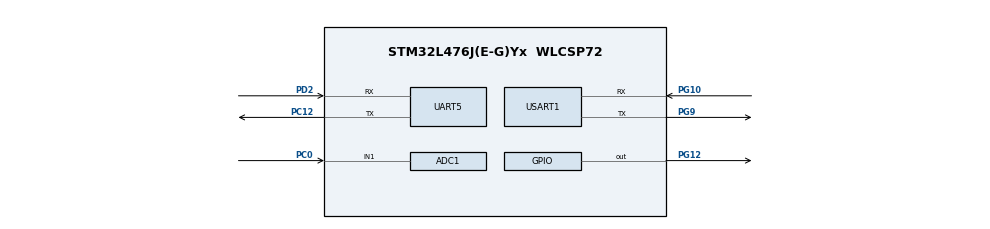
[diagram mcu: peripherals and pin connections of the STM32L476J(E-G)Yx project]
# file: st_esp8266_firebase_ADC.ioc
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ADC1.Channel-1\#ChannelRegularConversion=ADC_CHANNEL_1
ADC1.NbrOfConversionFlag=1
ADC1.OffsetNumber-1\#ChannelRegularConversion=ADC_OFFSET_NONE
ADC1.Rank-1\#ChannelRegularConversion=1
ADC1.SamplingTime-1\#ChannelRegularConversion=ADC_SAMPLETIME_2CYCLES_5
ADC1.master=1
Mcu.Family=STM32L4
Mcu.Name=STM32L476J(E-G)Yx
Mcu.Package=WLCSP72
NVIC.PriorityGroup=NVIC_PRIORITYGROUP_4
NVIC.UART5_IRQn=true\:0\:0\:false\:false\:true\:true\:true
NVIC.USART1_IRQn=true\:0\:0\:false\:false\:true\:true\:true
PC0.Signal=ADCx_IN1
PC12.Mode=Asynchronous
PC12.Signal=UART5_TX
PD2.Mode=Asynchronous
PD2.Signal=UART5_RX
PG10.Mode=Asynchronous
PG10.Signal=USART1_RX
PG12.Signal=GPIO_Output
PG9.Mode=Asynchronous
PG9.Signal=USART1_TX
PH0-OSC_IN\ (PH0).Mode=HSE-External-Oscillator
PH0-OSC_IN\ (PH0).Signal=RCC_OSC_IN
PH1-OSC_OUT\ (PH1).Mode=HSE-External-Oscillator
PH1-OSC_OUT\ (PH1).Signal=RCC_OSC_OUT
ProjectManager.HeapSize=0x200
ProjectManager.StackSize=0x400
ProjectManager.TargetToolchain=SW4STM32
RCC.ADCFreq_Value=32000000
RCC.AHBFreq_Value=50000000
RCC.APB1Freq_Value=50000000
RCC.APB1TimFreq_Value=50000000
RCC.APB2Freq_Value=50000000
RCC.APB2TimFreq_Value=50000000
RCC.CortexFreq_Value=50000000
RCC.HCLKFreq_Value=50000000
RCC.HSE_VALUE=8000000
RCC.HSI_VALUE=16000000
RCC.LSE_VALUE=32768
RCC.MSI_VALUE=4000000
RCC.PLLN=25
RCC.PLLSAI1N=16
RCC.SYSCLKFreq_VALUE=50000000
RCC.SYSCLKSource=RCC_SYSCLKSOURCE_PLLCLK
RCC.USBFreq_Value=32000000
RCC.VCOOutputFreq_Value=100000000
SH.ADCx_IN1.0=ADC1_IN1,IN1-Single-Ended
USART1.VirtualMode-Asynchronous=VM_ASYNC
board=custom

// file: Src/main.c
/* USER CODE BEGIN Header */
/**
 ******************************************************************************
 * @file           : main.c
 * @brief          : Main program body
 ******************************************************************************
 * @attention
 *
 * <h2><center>&copy; Copyright (c) 2020 STMicroelectronics.
 * All rights reserved.</center></h2>
 *
 * This software component is licensed by ST under BSD 3-Clause license,
 * the "License"; You may not use this file except in compliance with the
 * License. You may obtain a copy of the License at:
 *                        opensource.org/licenses/BSD-3-Clause
 *
 ******************************************************************************
 */
/* USER CODE END Header */

#include "main.h"
#include "ESPDataLogger.h"

ADC_HandleTypeDef hadc1;

UART_HandleTypeDef huart5;
UART_HandleTypeDef huart1;

void SystemClock_Config(void);
static void MX_GPIO_Init(void);
static void MX_ADC1_Init(void);
static void MX_USART1_UART_Init(void);
static void MX_UART5_Init(void);

/* USER CODE BEGIN 0 */
uint16_t ADC_Get_Value(void);

float Voltage = 0;
uint16_t ADC_Value = 0;
uint8_t count = 0;

uint16_t Value_Buf[4];

/* USER CODE END 0 */

int main(void) {

    /* MCU Configuration--------------------------------------------------------*/

    /* Reset of all peripherals, Initializes the Flash interface and the Systick. */
    HAL_Init();

    /* Configure the system clock */
    SystemClock_Config();

    /* Initialize all configured peripherals */
    MX_GPIO_Init();
    MX_ADC1_Init();
    MX_USART1_UART_Init();
    MX_UART5_Init();
    /* USER CODE BEGIN 2 */
    ESP_Init("test", "12345678");
    /* USER CODE END 2 */

    /* Infinite loop */
    while (1) {

        /* USER CODE BEGIN 3 */
        ADC_Value = ADC_Get_Value();
        Voltage = ((float) ADC_Value * 3.3 / 4095);
        count++;
        Value_Buf[0] = ADC_Value;
        Value_Buf[1] = Voltage;
        Value_Buf[2] = count;
        Value_Buf[3] = count * 2;

        ESP_Send_Multi(Value_Buf);

//        HAL_Delay(15000);
    }
    /* USER CODE END 3 */
}

void SystemClock_Config(void) {
    RCC_OscInitTypeDef RCC_OscInitStruct = { 0 };
    RCC_ClkInitTypeDef RCC_ClkInitStruct = { 0 };
    RCC_PeriphCLKInitTypeDef PeriphClkInit = { 0 };

    /** Initializes the CPU, AHB and APB busses clocks
     */
    RCC_OscInitStruct.OscillatorType = RCC_OSCILLATORTYPE_MSI;
    RCC_OscInitStruct.MSIState = RCC_MSI_ON;
    RCC_OscInitStruct.MSICalibrationValue = 0;
    RCC_OscInitStruct.MSIClockRange = RCC_MSIRANGE_6;
    RCC_OscInitStruct.PLL.PLLState = RCC_PLL_ON;
    RCC_OscInitStruct.PLL.PLLSource = RCC_PLLSOURCE_MSI;
    RCC_OscInitStruct.PLL.PLLM = 1;
    RCC_OscInitStruct.PLL.PLLN = 25;
    RCC_OscInitStruct.PLL.PLLP = RCC_PLLP_DIV7;
    RCC_OscInitStruct.PLL.PLLQ = RCC_PLLQ_DIV2;
    RCC_OscInitStruct.PLL.PLLR = RCC_PLLR_DIV2;
    if (HAL_RCC_OscConfig(&RCC_OscInitStruct) != HAL_OK) {
        Error_Handler();
    }
    /** Initializes the CPU, AHB and APB busses clocks
     */
    RCC_ClkInitStruct.ClockType = RCC_CLOCKTYPE_HCLK | RCC_CLOCKTYPE_SYSCLK
            | RCC_CLOCKTYPE_PCLK1 | RCC_CLOCKTYPE_PCLK2;
    RCC_ClkInitStruct.SYSCLKSource = RCC_SYSCLKSOURCE_PLLCLK;
    RCC_ClkInitStruct.AHBCLKDivider = RCC_SYSCLK_DIV2;
    RCC_ClkInitStruct.APB1CLKDivider = RCC_HCLK_DIV1;
    RCC_ClkInitStruct.APB2CLKDivider = RCC_HCLK_DIV1;

    if (HAL_RCC_ClockConfig(&RCC_ClkInitStruct, FLASH_LATENCY_1) != HAL_OK) {
        Error_Handler();
    }
    PeriphClkInit.PeriphClockSelection = RCC_PERIPHCLK_USART1
            | RCC_PERIPHCLK_UART5 | RCC_PERIPHCLK_ADC;
    PeriphClkInit.Usart1ClockSelection = RCC_USART1CLKSOURCE_PCLK2;
    PeriphClkInit.Uart5ClockSelection = RCC_UART5CLKSOURCE_PCLK1;
    PeriphClkInit.AdcClockSelection = RCC_ADCCLKSOURCE_PLLSAI1;
    PeriphClkInit.PLLSAI1.PLLSAI1Source = RCC_PLLSOURCE_MSI;
    PeriphClkInit.PLLSAI1.PLLSAI1M = 1;
    PeriphClkInit.PLLSAI1.PLLSAI1N = 16;
    PeriphClkInit.PLLSAI1.PLLSAI1P = RCC_PLLP_DIV7;
    PeriphClkInit.PLLSAI1.PLLSAI1Q = RCC_PLLQ_DIV2;
    PeriphClkInit.PLLSAI1.PLLSAI1R = RCC_PLLR_DIV2;
    PeriphClkInit.PLLSAI1.PLLSAI1ClockOut = RCC_PLLSAI1_ADC1CLK;
    if (HAL_RCCEx_PeriphCLKConfig(&PeriphClkInit) != HAL_OK) {
        Error_Handler();
    }
    /** Configure the main internal regulator output voltage
     */
    if (HAL_PWREx_ControlVoltageScaling(PWR_REGULATOR_VOLTAGE_SCALE1)
            != HAL_OK) {
        Error_Handler();
    }
}

static void MX_ADC1_Init(void) {

    ADC_MultiModeTypeDef multimode = { 0 };
    ADC_ChannelConfTypeDef sConfig = { 0 };

    /** Common config
     */
    hadc1.Instance = ADC1;
    hadc1.Init.ClockPrescaler = ADC_CLOCK_ASYNC_DIV1;
    hadc1.Init.Resolution = ADC_RESOLUTION_12B;
    hadc1.Init.DataAlign = ADC_DATAALIGN_RIGHT;
    hadc1.Init.ScanConvMode = ADC_SCAN_DISABLE;
    hadc1.Init.EOCSelection = ADC_EOC_SINGLE_CONV;
    hadc1.Init.LowPowerAutoWait = DISABLE;
    hadc1.Init.ContinuousConvMode = DISABLE;
    hadc1.Init.NbrOfConversion = 1;
    hadc1.Init.DiscontinuousConvMode = DISABLE;
    hadc1.Init.NbrOfDiscConversion = 1;
    hadc1.Init.ExternalTrigConv = ADC_SOFTWARE_START;
    hadc1.Init.ExternalTrigConvEdge = ADC_EXTERNALTRIGCONVEDGE_NONE;
    hadc1.Init.DMAContinuousRequests = DISABLE;
    hadc1.Init.Overrun = ADC_OVR_DATA_PRESERVED;
    hadc1.Init.OversamplingMode = DISABLE;
    if (HAL_ADC_Init(&hadc1) != HAL_OK) {
        Error_Handler();
    }
    /** Configure the ADC multi-mode
     */
    multimode.Mode = ADC_MODE_INDEPENDENT;
    if (HAL_ADCEx_MultiModeConfigChannel(&hadc1, &multimode) != HAL_OK) {
        Error_Handler();
    }
    /** Configure Regular Channel
     */
    sConfig.Channel = ADC_CHANNEL_1;
    sConfig.Rank = ADC_REGULAR_RANK_1;
    sConfig.SamplingTime = ADC_SAMPLETIME_2CYCLES_5;
    sConfig.SingleDiff = ADC_SINGLE_ENDED;
    sConfig.OffsetNumber = ADC_OFFSET_NONE;
    sConfig.Offset = 0;
    if (HAL_ADC_ConfigChannel(&hadc1, &sConfig) != HAL_OK) {
        Error_Handler();
    }

}

static void MX_UART5_Init(void) {

    huart5.Instance = UART5;
    huart5.Init.BaudRate = 115200;
    huart5.Init.WordLength = UART_WORDLENGTH_8B;
    huart5.Init.StopBits = UART_STOPBITS_1;
    huart5.Init.Parity = UART_PARITY_NONE;
    huart5.Init.Mode = UART_MODE_TX_RX;
    huart5.Init.HwFlowCtl = UART_HWCONTROL_NONE;
    huart5.Init.OverSampling = UART_OVERSAMPLING_16;
    huart5.Init.OneBitSampling = UART_ONE_BIT_SAMPLE_DISABLE;
    huart5.AdvancedInit.AdvFeatureInit = UART_ADVFEATURE_NO_INIT;
    if (HAL_UART_Init(&huart5) != HAL_OK) {
        Error_Handler();
    }

}

static void MX_USART1_UART_Init(void) {

    huart1.Instance = USART1;
    huart1.Init.BaudRate = 115200;
    huart1.Init.WordLength = UART_WORDLENGTH_8B;
    huart1.Init.StopBits = UART_STOPBITS_1;
    huart1.Init.Parity = UART_PARITY_NONE;
    huart1.Init.Mode = UART_MODE_TX_RX;
    huart1.Init.HwFlowCtl = UART_HWCONTROL_NONE;
    huart1.Init.OverSampling = UART_OVERSAMPLING_16;
    huart1.Init.OneBitSampling = UART_ONE_BIT_SAMPLE_DISABLE;
    huart1.AdvancedInit.AdvFeatureInit = UART_ADVFEATURE_NO_INIT;
    if (HAL_UART_Init(&huart1) != HAL_OK) {
        Error_Handler();
    }

}

static void MX_GPIO_Init(void) {

    /* GPIO Ports Clock Enable */
    __HAL_RCC_GPIOD_CLK_ENABLE()
    ;
    __HAL_RCC_GPIOG_CLK_ENABLE()
    ;
    HAL_PWREx_EnableVddIO2();
    __HAL_RCC_GPIOC_CLK_ENABLE()
    ;
    __HAL_RCC_GPIOH_CLK_ENABLE()
    ;

}

/* USER CODE BEGIN 4 */
uint16_t ADC_Get_Value(void) {
    uint16_t val = 0;
    HAL_ADC_Start(&hadc1);
    HAL_ADC_PollForConversion(&hadc1, 100);
    val = HAL_ADC_GetValue(&hadc1);
    HAL_ADC_Stop(&hadc1);
    return val;
}
/* USER CODE END 4 */

void Error_Handler(void) {
}

/************************ (C) COPYRIGHT STMicroelectronics *****END OF FILE****/
